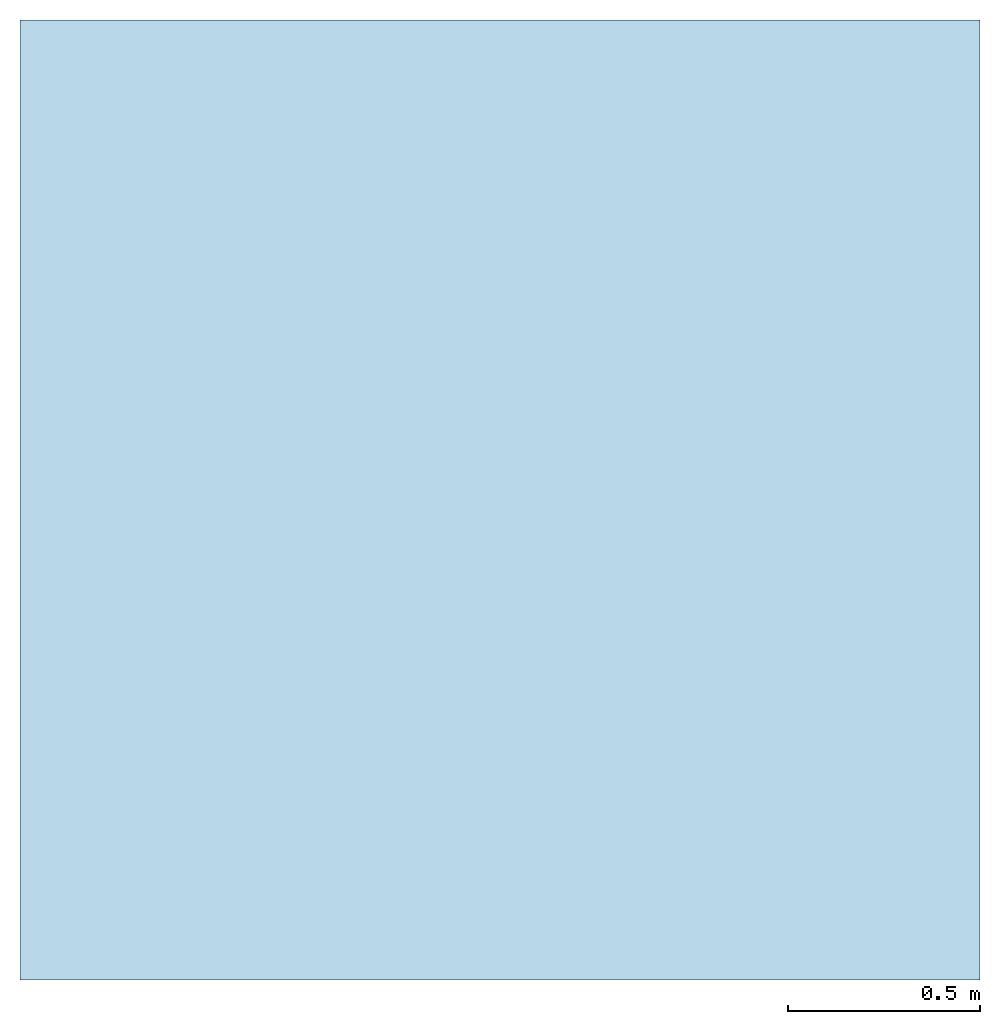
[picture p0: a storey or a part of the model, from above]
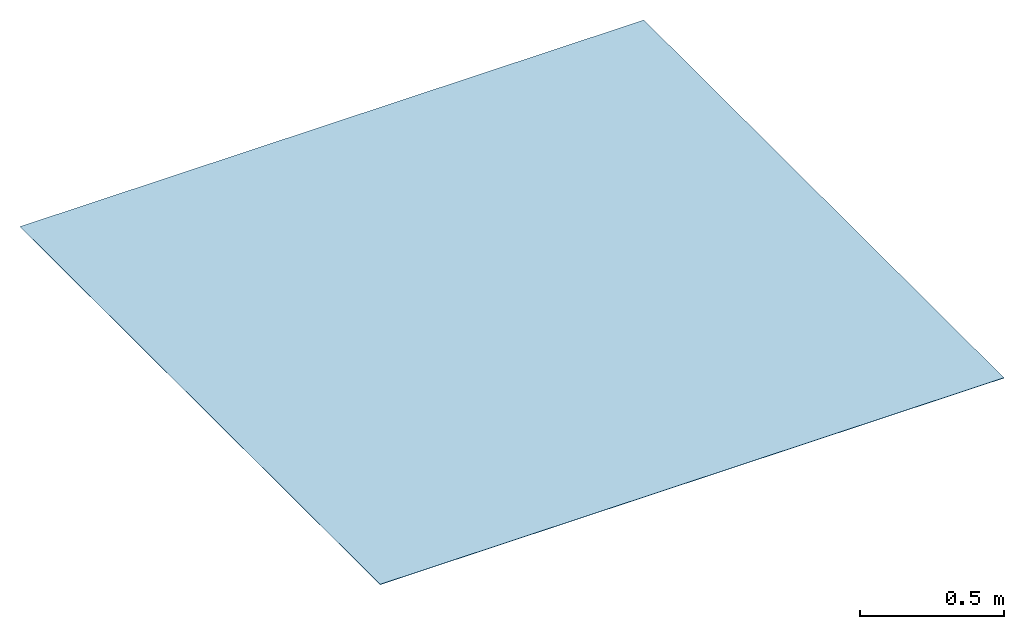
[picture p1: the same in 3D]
Properties of the parts of a building model (IFC2X3)

# File
Description: ViewDefinition[CoordinationView]
Time: 2017-03-02T10:28:20
Author: NBS
Written by: Xbim.Ifc File Processor version 2.4.1.0
Made in: Xbim version 2.4.1.0
Authorization: Add company name here

# IfcSlab: NBS_DeltaMembranes_PlasticsSheets_DELTA-GasBarrierSystem
In: Default building
Type - PredefinedType: ROOF; Material: NBS_DeltaMembranes_PlasticsSheets_DELTA-GasBarrierSystem 1.6 mm
Type - xbim_MaterialFunctionAssignment - MaterialFunctionAssignment: 0: Substrate
Type - COBie - AccessibilityPerformance: n/a; AssetType: Fixed; Category: Pr_25_57_65_60:Plastics sheets; CodePerformance: BR 211, BR 212 and Building Regulations Document C; Color: n/a; Constituents: n/a; Description: A high performance polymeric radon, CO2, and damp proof membrane; DurationUnit: year; ExpectedLife: n/a; Features: n/a; Grade: n/a; Manufacturer: info@deltamembranes.com; ModelNumber: n/a; ModelReference: DELTA®-Gas Barrier System; Name: PlasticsSheets_DELTA-GasBarrierSystem_DeltaMembranes; NominalHeight: 0 mm; NominalLength: 0 mm; NominalWidth: 0 mm; ReplacementCost: n/a; Shape: n/a; Size: n/a; SustainabilityPerformance: n/a; WarrantyDescription: n/a; WarrantyDurationLabor: n/a; WarrantyDurationParts: n/a; WarrantyDurationUnit: year; WarrantyGuarantorLabor: n/a; WarrantyGuarantorParts: n/a
Type - Pset_CoveringCommon - AcousticRating: n/a; Combustible: no; Finish: n/a; FireRating: n/a; FlammabilityRating: n/a; FragilityRating: n/a; Material: n/a; Reference: n/a; SurfaceSpreadOfFlame: n/a; TotalThickness: 0
Type - NBS_General - Author: NBS; BIMObjectName: NBS_DeltaMembranes_PlasticsSheets_DELTA-GasBarrierSystem; ManufacturerName: Delta Membrane Systems Ltd; ManufacturerURL: www.deltamembranes.com/; NBSCertification: www.nationalbimlibrary.com/cert/1rmhh4wf; NBSDescription: Plastics sheets; NBSNote: n/a; NBSOfficeMasterTag: n/a; NBSReference: 45-65-50/325; NBSTypeID: n/a; ProductInformation: www.deltamembranes.com/pdf/Delta%20Gas%20Barrier%20System_03.04.07.pdf; Revision: n/a; Uniclass2015Code: Pr_25_57_65_60; Uniclass2015Title: Plastics sheets; Uniclass2015Version: Products v1.4; Version: 5
Type - NBS_Data - Certification: n/a; PerformanceCriteria: n/a; RollSize: 4 x 25 m; RollWidth: 4000 mm; StandardThickness: 0.4 mm; TearResistance: n/a; TensileStrength: n/a; Weight: n/a
COBie - AssetIdentifier: n/a; BarCode: n/a; InstallationDate: 1900-12-31T23:59:59; SerialNumber: n/a; TagNumber: n/a; WarrantyStartDate: 1900-12-31T23:59:59
